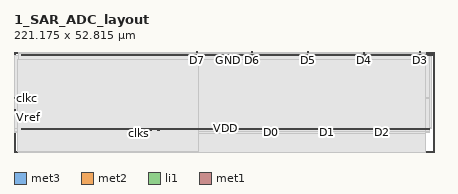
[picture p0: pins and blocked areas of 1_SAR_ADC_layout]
MACRO 1_SAR_ADC_layout
  CLASS BLOCK ;
  FOREIGN 1_SAR_ADC_layout ;
  ORIGIN 71.780 15.925 ;
  SIZE 221.175 BY 52.815 ;
  PIN D6
    ANTENNAGATEAREA 3.390000 ;
    ANTENNADIFFAREA 1.242000 ;
    PORT
      LAYER met3 ;
        RECT 53.305 36.540 53.905 36.890 ;
    END
  END D6
  PIN D5
    ANTENNAGATEAREA 3.390000 ;
    ANTENNADIFFAREA 1.242000 ;
    PORT
      LAYER met3 ;
        RECT 82.790 36.540 83.390 36.890 ;
    END
  END D5
  PIN D3
    ANTENNAGATEAREA 3.390000 ;
    ANTENNADIFFAREA 1.242000 ;
    PORT
      LAYER met3 ;
        RECT 141.710 36.535 142.310 36.885 ;
    END
  END D3
  PIN D7
    ANTENNAGATEAREA 2.040000 ;
    ANTENNADIFFAREA 1.242000 ;
    PORT
      LAYER met3 ;
        RECT 24.335 36.535 24.935 36.885 ;
    END
  END D7
  PIN clk_sar
    ANTENNAGATEAREA 12.150000 ;
    PORT
      LAYER met2 ;
        RECT -0.285 -4.605 0.545 -3.900 ;
    END
  END clk_sar
  PIN VDD
    ANTENNAGATEAREA 0.150000 ;
    ANTENNADIFFAREA 272.475586 ;
    PORT
      LAYER li1 ;
        RECT -67.715 -4.050 147.245 -3.370 ;
    END
  END VDD
  PIN Vin
    ANTENNADIFFAREA 0.330000 ;
    PORT
      LAYER met2 ;
        RECT 3.850 -4.615 4.680 -3.910 ;
    END
  END Vin
  PIN GND
    ANTENNAGATEAREA 17.820000 ;
    ANTENNADIFFAREA 261.296783 ;
    PORT
      LAYER li1 ;
        RECT -67.715 34.780 149.395 35.680 ;
    END
  END GND
  PIN D0
    ANTENNAGATEAREA 3.390000 ;
    ANTENNADIFFAREA 1.242000 ;
    PORT
      LAYER met3 ;
        RECT 63.150 -5.985 63.645 -5.605 ;
    END
  END D0
  PIN D1
    ANTENNAGATEAREA 3.390000 ;
    ANTENNADIFFAREA 1.242000 ;
    PORT
      LAYER met3 ;
        RECT 92.540 -5.985 93.035 -5.605 ;
    END
  END D1
  PIN D2
    ANTENNAGATEAREA 3.390000 ;
    ANTENNADIFFAREA 1.242000 ;
    PORT
      LAYER met3 ;
        RECT 122.020 -5.985 122.515 -5.605 ;
    END
  END D2
  PIN Vref
    ANTENNADIFFAREA 6.960000 ;
    PORT
      LAYER met1 ;
        RECT -71.780 5.970 -71.215 6.690 ;
    END
  END Vref
  PIN clkc
    ANTENNAGATEAREA 0.900000 ;
    PORT
      LAYER met2 ;
        RECT -71.750 12.300 -71.350 12.700 ;
    END
  END clkc
  PIN D4
    ANTENNAGATEAREA 3.390000 ;
    ANTENNADIFFAREA 1.242000 ;
    PORT
      LAYER met3 ;
        RECT 112.240 33.160 112.760 36.650 ;
    END
  END D4
  PIN clks
    ANTENNAGATEAREA 36.540001 ;
    PORT
      LAYER met2 ;
        RECT -6.000 -6.350 -5.500 -5.900 ;
    END
  END clks
  OBS
      LAYER nwell ;
        RECT -68.550 -0.715 146.615 33.955 ;
      LAYER li1 ;
        RECT -69.675 34.610 -67.885 34.780 ;
        RECT -69.675 -3.200 147.970 34.610 ;
        RECT -69.675 -3.370 -67.885 -3.200 ;
        RECT 147.415 -3.370 147.970 -3.200 ;
      LAYER met1 ;
        RECT -71.215 6.970 146.425 34.965 ;
        RECT -70.935 5.690 146.425 6.970 ;
        RECT -71.215 -5.540 146.425 5.690 ;
      LAYER met2 ;
        RECT -71.350 12.980 146.900 35.015 ;
        RECT -71.070 12.020 146.900 12.980 ;
        RECT -71.350 -3.620 146.900 12.020 ;
        RECT -71.350 -4.885 -0.565 -3.620 ;
        RECT 0.825 -3.630 146.900 -3.620 ;
        RECT 0.825 -4.885 3.570 -3.630 ;
        RECT -71.350 -4.895 3.570 -4.885 ;
        RECT 4.960 -4.895 146.900 -3.630 ;
        RECT -71.350 -5.620 146.900 -4.895 ;
        RECT -71.350 -5.900 -6.280 -5.620 ;
        RECT -5.220 -5.900 146.900 -5.620 ;
      LAYER met3 ;
        RECT -69.350 36.135 23.935 36.650 ;
        RECT 25.335 36.140 52.905 36.650 ;
        RECT 54.305 36.140 82.390 36.650 ;
        RECT 83.790 36.140 111.840 36.650 ;
        RECT 25.335 36.135 111.840 36.140 ;
        RECT -69.350 32.760 111.840 36.135 ;
        RECT 113.160 36.135 141.310 36.650 ;
        RECT 142.710 36.135 144.780 36.650 ;
        RECT 113.160 32.760 144.780 36.135 ;
        RECT -69.350 -5.205 144.780 32.760 ;
        RECT -69.350 -6.385 62.750 -5.205 ;
        RECT 64.045 -6.385 92.140 -5.205 ;
        RECT 93.435 -6.385 121.620 -5.205 ;
        RECT 122.915 -6.385 144.780 -5.205 ;
        RECT -69.350 -15.925 144.780 -6.385 ;
      LAYER met4 ;
        RECT -69.750 -15.865 25.170 32.610 ;
  END
END 1_SAR_ADC_layout
END LIBRARY

